# Generated by FakeRAM 2.0
VERSION 5.7 ;
BUSBITCHARS "[]" ;
PROPERTYDEFINITIONS
  MACRO width INTEGER ;
  MACRO depth INTEGER ;
  MACRO banks INTEGER ;
END PROPERTYDEFINITIONS
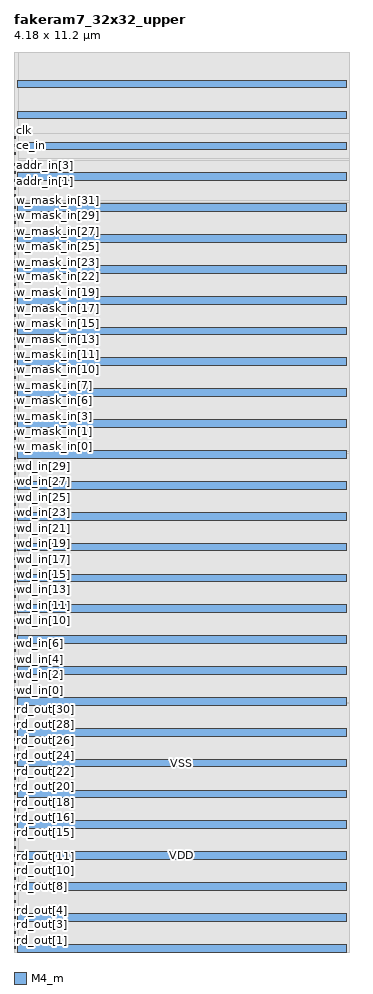
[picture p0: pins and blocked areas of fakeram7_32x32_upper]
MACRO fakeram7_32x32_upper
  PROPERTY width 32 ;
  PROPERTY depth 32 ;
  PROPERTY banks 2 ;
  FOREIGN fakeram7_32x32_upper 0 0 ;
  SYMMETRY X R90 ;
  SIZE 4.180 BY 11.200 ;
  CLASS COVER ;
  PIN rd_out[0]
    DIRECTION OUTPUT ;
    USE SIGNAL ;
    SHAPE ABUTMENT ;
    PORT
      LAYER M4_m ;
      RECT 0.000 0.039 0.024 0.063 ;
    END
  END rd_out[0]
  PIN rd_out[1]
    DIRECTION OUTPUT ;
    USE SIGNAL ;
    SHAPE ABUTMENT ;
    PORT
      LAYER M4_m ;
      RECT 0.000 0.135 0.024 0.159 ;
    END
  END rd_out[1]
  PIN rd_out[2]
    DIRECTION OUTPUT ;
    USE SIGNAL ;
    SHAPE ABUTMENT ;
    PORT
      LAYER M4_m ;
      RECT 0.000 0.231 0.024 0.255 ;
    END
  END rd_out[2]
  PIN rd_out[3]
    DIRECTION OUTPUT ;
    USE SIGNAL ;
    SHAPE ABUTMENT ;
    PORT
      LAYER M4_m ;
      RECT 0.000 0.327 0.024 0.351 ;
    END
  END rd_out[3]
  PIN rd_out[4]
    DIRECTION OUTPUT ;
    USE SIGNAL ;
    SHAPE ABUTMENT ;
    PORT
      LAYER M4_m ;
      RECT 0.000 0.423 0.024 0.447 ;
    END
  END rd_out[4]
  PIN rd_out[5]
    DIRECTION OUTPUT ;
    USE SIGNAL ;
    SHAPE ABUTMENT ;
    PORT
      LAYER M4_m ;
      RECT 0.000 0.519 0.024 0.543 ;
    END
  END rd_out[5]
  PIN rd_out[6]
    DIRECTION OUTPUT ;
    USE SIGNAL ;
    SHAPE ABUTMENT ;
    PORT
      LAYER M4_m ;
      RECT 0.000 0.615 0.024 0.639 ;
    END
  END rd_out[6]
  PIN rd_out[7]
    DIRECTION OUTPUT ;
    USE SIGNAL ;
    SHAPE ABUTMENT ;
    PORT
      LAYER M4_m ;
      RECT 0.000 0.711 0.024 0.735 ;
    END
  END rd_out[7]
  PIN rd_out[8]
    DIRECTION OUTPUT ;
    USE SIGNAL ;
    SHAPE ABUTMENT ;
    PORT
      LAYER M4_m ;
      RECT 0.000 0.807 0.024 0.831 ;
    END
  END rd_out[8]
  PIN rd_out[9]
    DIRECTION OUTPUT ;
    USE SIGNAL ;
    SHAPE ABUTMENT ;
    PORT
      LAYER M4_m ;
      RECT 0.000 0.903 0.024 0.927 ;
    END
  END rd_out[9]
  PIN rd_out[10]
    DIRECTION OUTPUT ;
    USE SIGNAL ;
    SHAPE ABUTMENT ;
    PORT
      LAYER M4_m ;
      RECT 0.000 0.999 0.024 1.023 ;
    END
  END rd_out[10]
  PIN rd_out[11]
    DIRECTION OUTPUT ;
    USE SIGNAL ;
    SHAPE ABUTMENT ;
    PORT
      LAYER M4_m ;
      RECT 0.000 1.095 0.024 1.119 ;
    END
  END rd_out[11]
  PIN rd_out[12]
    DIRECTION OUTPUT ;
    USE SIGNAL ;
    SHAPE ABUTMENT ;
    PORT
      LAYER M4_m ;
      RECT 0.000 1.191 0.024 1.215 ;
    END
  END rd_out[12]
  PIN rd_out[13]
    DIRECTION OUTPUT ;
    USE SIGNAL ;
    SHAPE ABUTMENT ;
    PORT
      LAYER M4_m ;
      RECT 0.000 1.287 0.024 1.311 ;
    END
  END rd_out[13]
  PIN rd_out[14]
    DIRECTION OUTPUT ;
    USE SIGNAL ;
    SHAPE ABUTMENT ;
    PORT
      LAYER M4_m ;
      RECT 0.000 1.383 0.024 1.407 ;
    END
  END rd_out[14]
  PIN rd_out[15]
    DIRECTION OUTPUT ;
    USE SIGNAL ;
    SHAPE ABUTMENT ;
    PORT
      LAYER M4_m ;
      RECT 0.000 1.479 0.024 1.503 ;
    END
  END rd_out[15]
  PIN rd_out[16]
    DIRECTION OUTPUT ;
    USE SIGNAL ;
    SHAPE ABUTMENT ;
    PORT
      LAYER M4_m ;
      RECT 0.000 1.575 0.024 1.599 ;
    END
  END rd_out[16]
  PIN rd_out[17]
    DIRECTION OUTPUT ;
    USE SIGNAL ;
    SHAPE ABUTMENT ;
    PORT
      LAYER M4_m ;
      RECT 0.000 1.671 0.024 1.695 ;
    END
  END rd_out[17]
  PIN rd_out[18]
    DIRECTION OUTPUT ;
    USE SIGNAL ;
    SHAPE ABUTMENT ;
    PORT
      LAYER M4_m ;
      RECT 0.000 1.767 0.024 1.791 ;
    END
  END rd_out[18]
  PIN rd_out[19]
    DIRECTION OUTPUT ;
    USE SIGNAL ;
    SHAPE ABUTMENT ;
    PORT
      LAYER M4_m ;
      RECT 0.000 1.863 0.024 1.887 ;
    END
  END rd_out[19]
  PIN rd_out[20]
    DIRECTION OUTPUT ;
    USE SIGNAL ;
    SHAPE ABUTMENT ;
    PORT
      LAYER M4_m ;
      RECT 0.000 1.959 0.024 1.983 ;
    END
  END rd_out[20]
  PIN rd_out[21]
    DIRECTION OUTPUT ;
    USE SIGNAL ;
    SHAPE ABUTMENT ;
    PORT
      LAYER M4_m ;
      RECT 0.000 2.055 0.024 2.079 ;
    END
  END rd_out[21]
  PIN rd_out[22]
    DIRECTION OUTPUT ;
    USE SIGNAL ;
    SHAPE ABUTMENT ;
    PORT
      LAYER M4_m ;
      RECT 0.000 2.151 0.024 2.175 ;
    END
  END rd_out[22]
  PIN rd_out[23]
    DIRECTION OUTPUT ;
    USE SIGNAL ;
    SHAPE ABUTMENT ;
    PORT
      LAYER M4_m ;
      RECT 0.000 2.247 0.024 2.271 ;
    END
  END rd_out[23]
  PIN rd_out[24]
    DIRECTION OUTPUT ;
    USE SIGNAL ;
    SHAPE ABUTMENT ;
    PORT
      LAYER M4_m ;
      RECT 0.000 2.343 0.024 2.367 ;
    END
  END rd_out[24]
  PIN rd_out[25]
    DIRECTION OUTPUT ;
    USE SIGNAL ;
    SHAPE ABUTMENT ;
    PORT
      LAYER M4_m ;
      RECT 0.000 2.439 0.024 2.463 ;
    END
  END rd_out[25]
  PIN rd_out[26]
    DIRECTION OUTPUT ;
    USE SIGNAL ;
    SHAPE ABUTMENT ;
    PORT
      LAYER M4_m ;
      RECT 0.000 2.535 0.024 2.559 ;
    END
  END rd_out[26]
  PIN rd_out[27]
    DIRECTION OUTPUT ;
    USE SIGNAL ;
    SHAPE ABUTMENT ;
    PORT
      LAYER M4_m ;
      RECT 0.000 2.631 0.024 2.655 ;
    END
  END rd_out[27]
  PIN rd_out[28]
    DIRECTION OUTPUT ;
    USE SIGNAL ;
    SHAPE ABUTMENT ;
    PORT
      LAYER M4_m ;
      RECT 0.000 2.727 0.024 2.751 ;
    END
  END rd_out[28]
  PIN rd_out[29]
    DIRECTION OUTPUT ;
    USE SIGNAL ;
    SHAPE ABUTMENT ;
    PORT
      LAYER M4_m ;
      RECT 0.000 2.823 0.024 2.847 ;
    END
  END rd_out[29]
  PIN rd_out[30]
    DIRECTION OUTPUT ;
    USE SIGNAL ;
    SHAPE ABUTMENT ;
    PORT
      LAYER M4_m ;
      RECT 0.000 2.919 0.024 2.943 ;
    END
  END rd_out[30]
  PIN rd_out[31]
    DIRECTION OUTPUT ;
    USE SIGNAL ;
    SHAPE ABUTMENT ;
    PORT
      LAYER M4_m ;
      RECT 0.000 3.015 0.024 3.039 ;
    END
  END rd_out[31]
  PIN wd_in[0]
    DIRECTION INPUT ;
    USE SIGNAL ;
    SHAPE ABUTMENT ;
    PORT
      LAYER M4_m ;
      RECT 0.000 3.159 0.024 3.183 ;
    END
  END wd_in[0]
  PIN wd_in[1]
    DIRECTION INPUT ;
    USE SIGNAL ;
    SHAPE ABUTMENT ;
    PORT
      LAYER M4_m ;
      RECT 0.000 3.255 0.024 3.279 ;
    END
  END wd_in[1]
  PIN wd_in[2]
    DIRECTION INPUT ;
    USE SIGNAL ;
    SHAPE ABUTMENT ;
    PORT
      LAYER M4_m ;
      RECT 0.000 3.351 0.024 3.375 ;
    END
  END wd_in[2]
  PIN wd_in[3]
    DIRECTION INPUT ;
    USE SIGNAL ;
    SHAPE ABUTMENT ;
    PORT
      LAYER M4_m ;
      RECT 0.000 3.447 0.024 3.471 ;
    END
  END wd_in[3]
  PIN wd_in[4]
    DIRECTION INPUT ;
    USE SIGNAL ;
    SHAPE ABUTMENT ;
    PORT
      LAYER M4_m ;
      RECT 0.000 3.543 0.024 3.567 ;
    END
  END wd_in[4]
  PIN wd_in[5]
    DIRECTION INPUT ;
    USE SIGNAL ;
    SHAPE ABUTMENT ;
    PORT
      LAYER M4_m ;
      RECT 0.000 3.639 0.024 3.663 ;
    END
  END wd_in[5]
  PIN wd_in[6]
    DIRECTION INPUT ;
    USE SIGNAL ;
    SHAPE ABUTMENT ;
    PORT
      LAYER M4_m ;
      RECT 0.000 3.735 0.024 3.759 ;
    END
  END wd_in[6]
  PIN wd_in[7]
    DIRECTION INPUT ;
    USE SIGNAL ;
    SHAPE ABUTMENT ;
    PORT
      LAYER M4_m ;
      RECT 0.000 3.831 0.024 3.855 ;
    END
  END wd_in[7]
  PIN wd_in[8]
    DIRECTION INPUT ;
    USE SIGNAL ;
    SHAPE ABUTMENT ;
    PORT
      LAYER M4_m ;
      RECT 0.000 3.927 0.024 3.951 ;
    END
  END wd_in[8]
  PIN wd_in[9]
    DIRECTION INPUT ;
    USE SIGNAL ;
    SHAPE ABUTMENT ;
    PORT
      LAYER M4_m ;
      RECT 0.000 4.023 0.024 4.047 ;
    END
  END wd_in[9]
  PIN wd_in[10]
    DIRECTION INPUT ;
    USE SIGNAL ;
    SHAPE ABUTMENT ;
    PORT
      LAYER M4_m ;
      RECT 0.000 4.119 0.024 4.143 ;
    END
  END wd_in[10]
  PIN wd_in[11]
    DIRECTION INPUT ;
    USE SIGNAL ;
    SHAPE ABUTMENT ;
    PORT
      LAYER M4_m ;
      RECT 0.000 4.215 0.024 4.239 ;
    END
  END wd_in[11]
  PIN wd_in[12]
    DIRECTION INPUT ;
    USE SIGNAL ;
    SHAPE ABUTMENT ;
    PORT
      LAYER M4_m ;
      RECT 0.000 4.311 0.024 4.335 ;
    END
  END wd_in[12]
  PIN wd_in[13]
    DIRECTION INPUT ;
    USE SIGNAL ;
    SHAPE ABUTMENT ;
    PORT
      LAYER M4_m ;
      RECT 0.000 4.407 0.024 4.431 ;
    END
  END wd_in[13]
  PIN wd_in[14]
    DIRECTION INPUT ;
    USE SIGNAL ;
    SHAPE ABUTMENT ;
    PORT
      LAYER M4_m ;
      RECT 0.000 4.503 0.024 4.527 ;
    END
  END wd_in[14]
  PIN wd_in[15]
    DIRECTION INPUT ;
    USE SIGNAL ;
    SHAPE ABUTMENT ;
    PORT
      LAYER M4_m ;
      RECT 0.000 4.599 0.024 4.623 ;
    END
  END wd_in[15]
  PIN wd_in[16]
    DIRECTION INPUT ;
    USE SIGNAL ;
    SHAPE ABUTMENT ;
    PORT
      LAYER M4_m ;
      RECT 0.000 4.695 0.024 4.719 ;
    END
  END wd_in[16]
  PIN wd_in[17]
    DIRECTION INPUT ;
    USE SIGNAL ;
    SHAPE ABUTMENT ;
    PORT
      LAYER M4_m ;
      RECT 0.000 4.791 0.024 4.815 ;
    END
  END wd_in[17]
  PIN wd_in[18]
    DIRECTION INPUT ;
    USE SIGNAL ;
    SHAPE ABUTMENT ;
    PORT
      LAYER M4_m ;
      RECT 0.000 4.887 0.024 4.911 ;
    END
  END wd_in[18]
  PIN wd_in[19]
    DIRECTION INPUT ;
    USE SIGNAL ;
    SHAPE ABUTMENT ;
    PORT
      LAYER M4_m ;
      RECT 0.000 4.983 0.024 5.007 ;
    END
  END wd_in[19]
  PIN wd_in[20]
    DIRECTION INPUT ;
    USE SIGNAL ;
    SHAPE ABUTMENT ;
    PORT
      LAYER M4_m ;
      RECT 0.000 5.079 0.024 5.103 ;
    END
  END wd_in[20]
  PIN wd_in[21]
    DIRECTION INPUT ;
    USE SIGNAL ;
    SHAPE ABUTMENT ;
    PORT
      LAYER M4_m ;
      RECT 0.000 5.175 0.024 5.199 ;
    END
  END wd_in[21]
  PIN wd_in[22]
    DIRECTION INPUT ;
    USE SIGNAL ;
    SHAPE ABUTMENT ;
    PORT
      LAYER M4_m ;
      RECT 0.000 5.271 0.024 5.295 ;
    END
  END wd_in[22]
  PIN wd_in[23]
    DIRECTION INPUT ;
    USE SIGNAL ;
    SHAPE ABUTMENT ;
    PORT
      LAYER M4_m ;
      RECT 0.000 5.367 0.024 5.391 ;
    END
  END wd_in[23]
  PIN wd_in[24]
    DIRECTION INPUT ;
    USE SIGNAL ;
    SHAPE ABUTMENT ;
    PORT
      LAYER M4_m ;
      RECT 0.000 5.463 0.024 5.487 ;
    END
  END wd_in[24]
  PIN wd_in[25]
    DIRECTION INPUT ;
    USE SIGNAL ;
    SHAPE ABUTMENT ;
    PORT
      LAYER M4_m ;
      RECT 0.000 5.559 0.024 5.583 ;
    END
  END wd_in[25]
  PIN wd_in[26]
    DIRECTION INPUT ;
    USE SIGNAL ;
    SHAPE ABUTMENT ;
    PORT
      LAYER M4_m ;
      RECT 0.000 5.655 0.024 5.679 ;
    END
  END wd_in[26]
  PIN wd_in[27]
    DIRECTION INPUT ;
    USE SIGNAL ;
    SHAPE ABUTMENT ;
    PORT
      LAYER M4_m ;
      RECT 0.000 5.751 0.024 5.775 ;
    END
  END wd_in[27]
  PIN wd_in[28]
    DIRECTION INPUT ;
    USE SIGNAL ;
    SHAPE ABUTMENT ;
    PORT
      LAYER M4_m ;
      RECT 0.000 5.847 0.024 5.871 ;
    END
  END wd_in[28]
  PIN wd_in[29]
    DIRECTION INPUT ;
    USE SIGNAL ;
    SHAPE ABUTMENT ;
    PORT
      LAYER M4_m ;
      RECT 0.000 5.943 0.024 5.967 ;
    END
  END wd_in[29]
  PIN wd_in[30]
    DIRECTION INPUT ;
    USE SIGNAL ;
    SHAPE ABUTMENT ;
    PORT
      LAYER M4_m ;
      RECT 0.000 6.039 0.024 6.063 ;
    END
  END wd_in[30]
  PIN wd_in[31]
    DIRECTION INPUT ;
    USE SIGNAL ;
    SHAPE ABUTMENT ;
    PORT
      LAYER M4_m ;
      RECT 0.000 6.135 0.024 6.159 ;
    END
  END wd_in[31]
  PIN w_mask_in[0]
    DIRECTION INPUT ;
    USE SIGNAL ;
    SHAPE ABUTMENT ;
    PORT
      LAYER M4_m ;
      RECT 0.000 6.279 0.024 6.303 ;
    END
  END w_mask_in[0]
  PIN w_mask_in[1]
    DIRECTION INPUT ;
    USE SIGNAL ;
    SHAPE ABUTMENT ;
    PORT
      LAYER M4_m ;
      RECT 0.000 6.375 0.024 6.399 ;
    END
  END w_mask_in[1]
  PIN w_mask_in[2]
    DIRECTION INPUT ;
    USE SIGNAL ;
    SHAPE ABUTMENT ;
    PORT
      LAYER M4_m ;
      RECT 0.000 6.471 0.024 6.495 ;
    END
  END w_mask_in[2]
  PIN w_mask_in[3]
    DIRECTION INPUT ;
    USE SIGNAL ;
    SHAPE ABUTMENT ;
    PORT
      LAYER M4_m ;
      RECT 0.000 6.567 0.024 6.591 ;
    END
  END w_mask_in[3]
  PIN w_mask_in[4]
    DIRECTION INPUT ;
    USE SIGNAL ;
    SHAPE ABUTMENT ;
    PORT
      LAYER M4_m ;
      RECT 0.000 6.663 0.024 6.687 ;
    END
  END w_mask_in[4]
  PIN w_mask_in[5]
    DIRECTION INPUT ;
    USE SIGNAL ;
    SHAPE ABUTMENT ;
    PORT
      LAYER M4_m ;
      RECT 0.000 6.759 0.024 6.783 ;
    END
  END w_mask_in[5]
  PIN w_mask_in[6]
    DIRECTION INPUT ;
    USE SIGNAL ;
    SHAPE ABUTMENT ;
    PORT
      LAYER M4_m ;
      RECT 0.000 6.855 0.024 6.879 ;
    END
  END w_mask_in[6]
  PIN w_mask_in[7]
    DIRECTION INPUT ;
    USE SIGNAL ;
    SHAPE ABUTMENT ;
    PORT
      LAYER M4_m ;
      RECT 0.000 6.951 0.024 6.975 ;
    END
  END w_mask_in[7]
  PIN w_mask_in[8]
    DIRECTION INPUT ;
    USE SIGNAL ;
    SHAPE ABUTMENT ;
    PORT
      LAYER M4_m ;
      RECT 0.000 7.047 0.024 7.071 ;
    END
  END w_mask_in[8]
  PIN w_mask_in[9]
    DIRECTION INPUT ;
    USE SIGNAL ;
    SHAPE ABUTMENT ;
    PORT
      LAYER M4_m ;
      RECT 0.000 7.143 0.024 7.167 ;
    END
  END w_mask_in[9]
  PIN w_mask_in[10]
    DIRECTION INPUT ;
    USE SIGNAL ;
    SHAPE ABUTMENT ;
    PORT
      LAYER M4_m ;
      RECT 0.000 7.239 0.024 7.263 ;
    END
  END w_mask_in[10]
  PIN w_mask_in[11]
    DIRECTION INPUT ;
    USE SIGNAL ;
    SHAPE ABUTMENT ;
    PORT
      LAYER M4_m ;
      RECT 0.000 7.335 0.024 7.359 ;
    END
  END w_mask_in[11]
  PIN w_mask_in[12]
    DIRECTION INPUT ;
    USE SIGNAL ;
    SHAPE ABUTMENT ;
    PORT
      LAYER M4_m ;
      RECT 0.000 7.431 0.024 7.455 ;
    END
  END w_mask_in[12]
  PIN w_mask_in[13]
    DIRECTION INPUT ;
    USE SIGNAL ;
    SHAPE ABUTMENT ;
    PORT
      LAYER M4_m ;
      RECT 0.000 7.527 0.024 7.551 ;
    END
  END w_mask_in[13]
  PIN w_mask_in[14]
    DIRECTION INPUT ;
    USE SIGNAL ;
    SHAPE ABUTMENT ;
    PORT
      LAYER M4_m ;
      RECT 0.000 7.623 0.024 7.647 ;
    END
  END w_mask_in[14]
  PIN w_mask_in[15]
    DIRECTION INPUT ;
    USE SIGNAL ;
    SHAPE ABUTMENT ;
    PORT
      LAYER M4_m ;
      RECT 0.000 7.719 0.024 7.743 ;
    END
  END w_mask_in[15]
  PIN w_mask_in[16]
    DIRECTION INPUT ;
    USE SIGNAL ;
    SHAPE ABUTMENT ;
    PORT
      LAYER M4_m ;
      RECT 0.000 7.815 0.024 7.839 ;
    END
  END w_mask_in[16]
  PIN w_mask_in[17]
    DIRECTION INPUT ;
    USE SIGNAL ;
    SHAPE ABUTMENT ;
    PORT
      LAYER M4_m ;
      RECT 0.000 7.911 0.024 7.935 ;
    END
  END w_mask_in[17]
  PIN w_mask_in[18]
    DIRECTION INPUT ;
    USE SIGNAL ;
    SHAPE ABUTMENT ;
    PORT
      LAYER M4_m ;
      RECT 0.000 8.007 0.024 8.031 ;
    END
  END w_mask_in[18]
  PIN w_mask_in[19]
    DIRECTION INPUT ;
    USE SIGNAL ;
    SHAPE ABUTMENT ;
    PORT
      LAYER M4_m ;
      RECT 0.000 8.103 0.024 8.127 ;
    END
  END w_mask_in[19]
  PIN w_mask_in[20]
    DIRECTION INPUT ;
    USE SIGNAL ;
    SHAPE ABUTMENT ;
    PORT
      LAYER M4_m ;
      RECT 0.000 8.199 0.024 8.223 ;
    END
  END w_mask_in[20]
  PIN w_mask_in[21]
    DIRECTION INPUT ;
    USE SIGNAL ;
    SHAPE ABUTMENT ;
    PORT
      LAYER M4_m ;
      RECT 0.000 8.295 0.024 8.319 ;
    END
  END w_mask_in[21]
  PIN w_mask_in[22]
    DIRECTION INPUT ;
    USE SIGNAL ;
    SHAPE ABUTMENT ;
    PORT
      LAYER M4_m ;
      RECT 0.000 8.391 0.024 8.415 ;
    END
  END w_mask_in[22]
  PIN w_mask_in[23]
    DIRECTION INPUT ;
    USE SIGNAL ;
    SHAPE ABUTMENT ;
    PORT
      LAYER M4_m ;
      RECT 0.000 8.487 0.024 8.511 ;
    END
  END w_mask_in[23]
  PIN w_mask_in[24]
    DIRECTION INPUT ;
    USE SIGNAL ;
    SHAPE ABUTMENT ;
    PORT
      LAYER M4_m ;
      RECT 0.000 8.583 0.024 8.607 ;
    END
  END w_mask_in[24]
  PIN w_mask_in[25]
    DIRECTION INPUT ;
    USE SIGNAL ;
    SHAPE ABUTMENT ;
    PORT
      LAYER M4_m ;
      RECT 0.000 8.679 0.024 8.703 ;
    END
  END w_mask_in[25]
  PIN w_mask_in[26]
    DIRECTION INPUT ;
    USE SIGNAL ;
    SHAPE ABUTMENT ;
    PORT
      LAYER M4_m ;
      RECT 0.000 8.775 0.024 8.799 ;
    END
  END w_mask_in[26]
  PIN w_mask_in[27]
    DIRECTION INPUT ;
    USE SIGNAL ;
    SHAPE ABUTMENT ;
    PORT
      LAYER M4_m ;
      RECT 0.000 8.871 0.024 8.895 ;
    END
  END w_mask_in[27]
  PIN w_mask_in[28]
    DIRECTION INPUT ;
    USE SIGNAL ;
    SHAPE ABUTMENT ;
    PORT
      LAYER M4_m ;
      RECT 0.000 8.967 0.024 8.991 ;
    END
  END w_mask_in[28]
  PIN w_mask_in[29]
    DIRECTION INPUT ;
    USE SIGNAL ;
    SHAPE ABUTMENT ;
    PORT
      LAYER M4_m ;
      RECT 0.000 9.063 0.024 9.087 ;
    END
  END w_mask_in[29]
  PIN w_mask_in[30]
    DIRECTION INPUT ;
    USE SIGNAL ;
    SHAPE ABUTMENT ;
    PORT
      LAYER M4_m ;
      RECT 0.000 9.159 0.024 9.183 ;
    END
  END w_mask_in[30]
  PIN w_mask_in[31]
    DIRECTION INPUT ;
    USE SIGNAL ;
    SHAPE ABUTMENT ;
    PORT
      LAYER M4_m ;
      RECT 0.000 9.255 0.024 9.279 ;
    END
  END w_mask_in[31]
  PIN addr_in[0]
    DIRECTION INPUT ;
    USE SIGNAL ;
    SHAPE ABUTMENT ;
    PORT
      LAYER M4_m ;
      RECT 0.000 9.399 0.024 9.423 ;
    END
  END addr_in[0]
  PIN addr_in[1]
    DIRECTION INPUT ;
    USE SIGNAL ;
    SHAPE ABUTMENT ;
    PORT
      LAYER M4_m ;
      RECT 0.000 9.495 0.024 9.519 ;
    END
  END addr_in[1]
  PIN addr_in[2]
    DIRECTION INPUT ;
    USE SIGNAL ;
    SHAPE ABUTMENT ;
    PORT
      LAYER M4_m ;
      RECT 0.000 9.591 0.024 9.615 ;
    END
  END addr_in[2]
  PIN addr_in[3]
    DIRECTION INPUT ;
    USE SIGNAL ;
    SHAPE ABUTMENT ;
    PORT
      LAYER M4_m ;
      RECT 0.000 9.687 0.024 9.711 ;
    END
  END addr_in[3]
  PIN addr_in[4]
    DIRECTION INPUT ;
    USE SIGNAL ;
    SHAPE ABUTMENT ;
    PORT
      LAYER M4_m ;
      RECT 0.000 9.783 0.024 9.807 ;
    END
  END addr_in[4]
  PIN we_in
    DIRECTION INPUT ;
    USE SIGNAL ;
    SHAPE ABUTMENT ;
    PORT
      LAYER M4_m ;
      RECT 0.000 9.927 0.024 9.951 ;
    END
  END we_in
  PIN ce_in
    DIRECTION INPUT ;
    USE SIGNAL ;
    SHAPE ABUTMENT ;
    PORT
      LAYER M4_m ;
      RECT 0.000 10.023 0.024 10.047 ;
    END
  END ce_in
  PIN clk
    DIRECTION INPUT ;
    USE SIGNAL ;
    SHAPE ABUTMENT ;
    PORT
      LAYER M4_m ;
      RECT 0.000 10.119 0.024 10.143 ;
    END
  END clk
  PIN VSS
    DIRECTION INOUT ;
    USE GROUND ;
    PORT
      LAYER M4_m ;
      RECT 0.048 0.000 4.132 0.096 ;
      RECT 0.048 0.768 4.132 0.864 ;
      RECT 0.048 1.536 4.132 1.632 ;
      RECT 0.048 2.304 4.132 2.400 ;
      RECT 0.048 3.072 4.132 3.168 ;
      RECT 0.048 3.840 4.132 3.936 ;
      RECT 0.048 4.608 4.132 4.704 ;
      RECT 0.048 5.376 4.132 5.472 ;
      RECT 0.048 6.144 4.132 6.240 ;
      RECT 0.048 6.912 4.132 7.008 ;
      RECT 0.048 7.680 4.132 7.776 ;
      RECT 0.048 8.448 4.132 8.544 ;
      RECT 0.048 9.216 4.132 9.312 ;
      RECT 0.048 9.984 4.132 10.080 ;
      RECT 0.048 10.752 4.132 10.848 ;
    END
  END VSS
  PIN VDD
    DIRECTION INOUT ;
    USE POWER ;
    PORT
      LAYER M4_m ;
      RECT 0.048 0.384 4.132 0.480 ;
      RECT 0.048 1.152 4.132 1.248 ;
      RECT 0.048 1.920 4.132 2.016 ;
      RECT 0.048 2.688 4.132 2.784 ;
      RECT 0.048 3.456 4.132 3.552 ;
      RECT 0.048 4.224 4.132 4.320 ;
      RECT 0.048 4.992 4.132 5.088 ;
      RECT 0.048 5.760 4.132 5.856 ;
      RECT 0.048 6.528 4.132 6.624 ;
      RECT 0.048 7.296 4.132 7.392 ;
      RECT 0.048 8.064 4.132 8.160 ;
      RECT 0.048 8.832 4.132 8.928 ;
      RECT 0.048 9.600 4.132 9.696 ;
      RECT 0.048 10.368 4.132 10.464 ;
    END
  END VDD
  OBS
    LAYER M1_m ;
    RECT 0 0 4.180 11.200 ;
    LAYER M2_m ;
    RECT 0 0 4.180 11.200 ;
    LAYER M3_m ;
    RECT 0.059 0.000 4.180 11.200 ;
    LAYER M4_m ;
    RECT 0.059 3.087 4.180 3.111 ;
    RECT 0.059 6.207 4.180 6.231 ;
    RECT 0.059 9.327 4.180 9.351 ;
    RECT 0.059 9.855 4.180 9.879 ;
    RECT 0.059 10.191 4.180 11.200 ;
  END
END fakeram7_32x32_upper

END LIBRARY
